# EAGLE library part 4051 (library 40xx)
8-channel ANALOG MULTIPLEXER

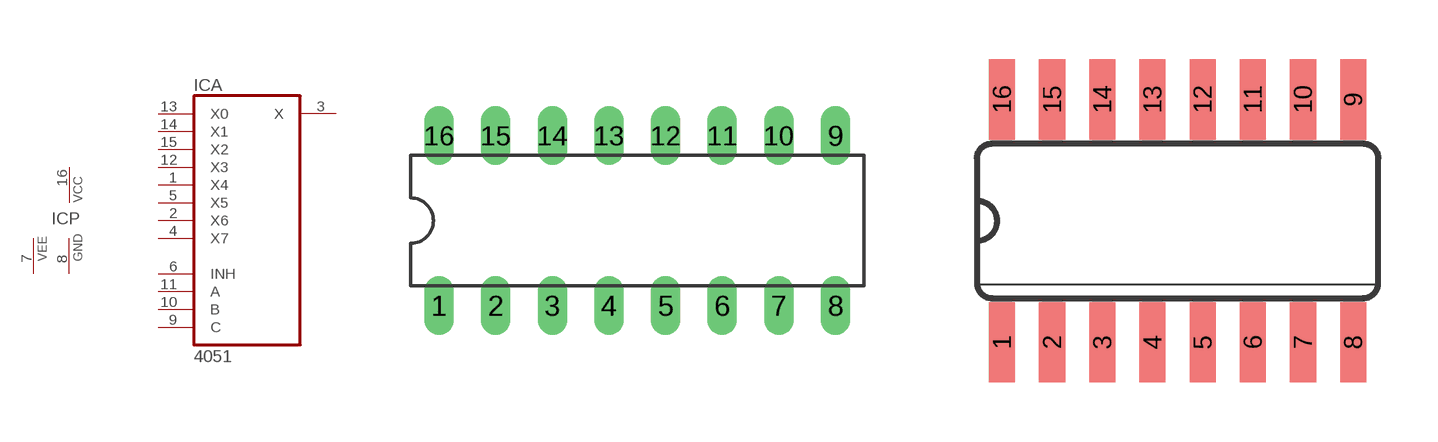
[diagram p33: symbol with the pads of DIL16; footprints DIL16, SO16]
Designator prefix IC; gates A=4051 P=PWR+VEE

## 4051N  [DIL16]
1  A:X4
2  A:X6
3  A:X
4  A:X7
5  A:X5
6  A:INH  in
7  P:VEE  pwr
8  P:GND  pwr
9  A:C  in
10  A:B  in
11  A:A  in
12  A:X3
13  A:X0
14  A:X1
15  A:X2
16  P:VCC  pwr

## 4051D  [SO16]
Pads as for DIL16

## Footprint DIL16 (pad centres in mm)
Dual In Line Package
drill 0.813 long: 1 -8.89,-3.81; 2 -6.35,-3.81; 3 -3.81,-3.81; 4 -1.27,-3.81; 5 1.27,-3.81; 6 3.81,-3.81; 7 6.35,-3.81; 8 8.89,-3.81; 9 8.89,3.81; 10 6.35,3.81; 11 3.81,3.81; 12 1.27,3.81; 13 -1.27,3.81; 14 -3.81,3.81; 15 -6.35,3.81; 16 -8.89,3.81

## Footprint SO16 (pad centres in mm)
Small Outline package 150 mil
smd 0.66 x 2.032: 1 -4.445,-3.073; 2 -3.175,-3.073; 3 -1.905,-3.073; 4 -0.635,-3.073; 5 0.635,-3.073; 6 1.905,-3.073; 7 3.175,-3.073; 8 4.445,-3.073; 9 4.445,3.073; 10 3.175,3.073; 11 1.905,3.073; 12 0.635,3.073; 13 -0.635,3.073; 14 -1.905,3.073; 15 -3.175,3.073; 16 -4.445,3.073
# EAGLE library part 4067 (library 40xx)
16-channel ANALOG MULTIPLEXER

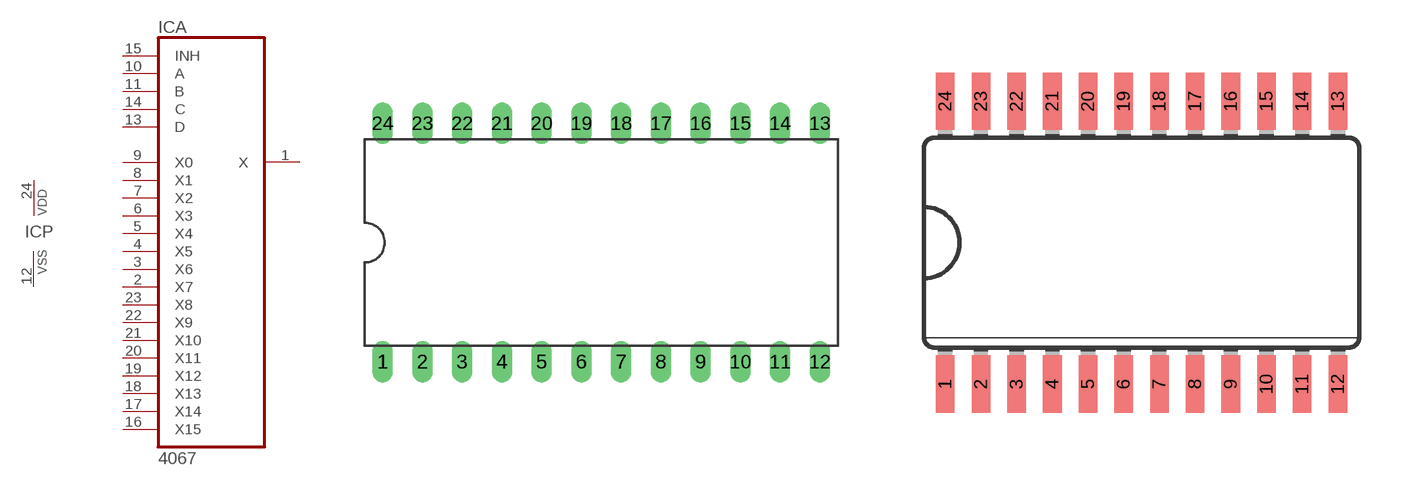
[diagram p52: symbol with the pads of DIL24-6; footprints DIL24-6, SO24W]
Designator prefix IC; gates A=4067 P=PWRN

## 4067N  [DIL24-6]
1  A:X  out
2  A:X7  in
3  A:X6  in
4  A:X5  in
5  A:X4  in
6  A:X3  in
7  A:X2  in
8  A:X1  in
9  A:X0  in
10  A:A  in
11  A:B  in
12  P:VSS  pwr
13  A:D  in
14  A:C  in
15  A:INH  in
16  A:X15  in
17  A:X14  in
18  A:X13  in
19  A:X12  in
20  A:X11  in
21  A:X10  in
22  A:X9  in
23  A:X8  in
24  P:VDD  pwr

## 4067D  [SO24W]
Pads as for DIL24-6

## Footprint DIL24-6 (pad centres in mm)
Dual In Line Package 0.6 inch
drill 0.813 long: 1 -13.97,-7.62; 2 -11.43,-7.62; 3 -8.89,-7.62; 4 -6.35,-7.62; 5 -3.81,-7.62; 6 -1.27,-7.62; 7 1.27,-7.62; 8 3.81,-7.62; 9 6.35,-7.62; 10 8.89,-7.62; 11 11.43,-7.62; 12 13.97,-7.62; 13 13.97,7.62; 14 11.43,7.62; 15 8.89,7.62; 16 6.35,7.62; 17 3.81,7.62; 18 1.27,7.62; 19 -1.27,7.62; 20 -3.81,7.62; 21 -6.35,7.62; 22 -8.89,7.62; 23 -11.43,7.62; 24 -13.97,7.62

## Footprint SO24W (pad centres in mm)
Wide Small Outline package 300 mil
smd 0.66 x 2.032: 1 -6.985,-5.029; 2 -5.715,-5.029; 3 -4.445,-5.029; 4 -3.175,-5.029; 5 -1.905,-5.029; 6 -0.635,-5.029; 7 0.635,-5.029; 8 1.905,-5.029; 9 3.175,-5.029; 10 4.445,-5.029; 11 5.715,-5.029; 12 6.985,-5.029; 13 6.985,5.029; 14 5.715,5.029; 15 4.445,5.029; 16 3.175,5.029; 17 1.905,5.029; 18 0.635,5.029; 19 -0.635,5.029; 20 -1.905,5.029; 21 -3.175,5.029; 22 -4.445,5.029; 23 -5.715,5.029; 24 -6.985,5.029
